VERSION 5.7 ;
  NOWIREEXTENSIONATPIN ON ;
  DIVIDERCHAR "/" ;
  BUSBITCHARS "[]" ;
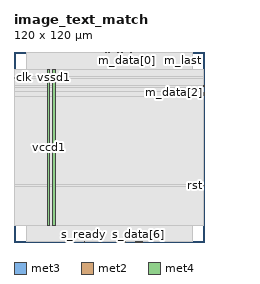
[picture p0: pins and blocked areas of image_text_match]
MACRO image_text_match
  CLASS BLOCK ;
  FOREIGN image_text_match ;
  ORIGIN 0.000 0.000 ;
  SIZE 120.000 BY 120.000 ;
  PIN clk
    DIRECTION INPUT ;
    USE SIGNAL ;
    ANTENNAGATEAREA 1.286700 ;
    ANTENNADIFFAREA 0.434700 ;
    PORT
      LAYER met3 ;
        RECT 0.000 103.400 0.600 104.000 ;
    END
  END clk
  PIN m_data[0]
    DIRECTION OUTPUT ;
    USE SIGNAL ;
    ANTENNADIFFAREA 0.702900 ;
    PORT
      LAYER met2 ;
        RECT 70.930 119.720 71.210 120.000 ;
    END
  END m_data[0]
  PIN m_data[1]
    DIRECTION OUTPUT ;
    USE SIGNAL ;
    ANTENNADIFFAREA 0.702900 ;
    PORT
      LAYER met2 ;
        RECT 68.170 119.720 68.450 120.000 ;
    END
  END m_data[1]
  PIN m_data[2]
    DIRECTION OUTPUT ;
    USE SIGNAL ;
    ANTENNADIFFAREA 0.702900 ;
    PORT
      LAYER met3 ;
        RECT 119.400 93.880 120.000 94.480 ;
    END
  END m_data[2]
  PIN m_data[3]
    DIRECTION OUTPUT ;
    USE SIGNAL ;
    ANTENNADIFFAREA 0.702900 ;
    PORT
      LAYER met3 ;
        RECT 119.400 92.520 120.000 93.120 ;
    END
  END m_data[3]
  PIN m_data[4]
    DIRECTION OUTPUT ;
    USE SIGNAL ;
    ANTENNADIFFAREA 0.702900 ;
    PORT
      LAYER met2 ;
        RECT 94.850 119.720 95.130 120.000 ;
    END
  END m_data[4]
  PIN m_data[5]
    DIRECTION OUTPUT ;
    USE SIGNAL ;
    ANTENNADIFFAREA 0.702900 ;
    PORT
      LAYER met3 ;
        RECT 119.400 97.960 120.000 98.560 ;
    END
  END m_data[5]
  PIN m_data[6]
    DIRECTION OUTPUT ;
    USE SIGNAL ;
    ANTENNADIFFAREA 0.702900 ;
    PORT
      LAYER met2 ;
        RECT 73.690 119.720 73.970 120.000 ;
    END
  END m_data[6]
  PIN m_data[7]
    DIRECTION OUTPUT ;
    USE SIGNAL ;
    ANTENNADIFFAREA 0.702900 ;
    PORT
      LAYER met2 ;
        RECT 72.770 119.720 73.050 120.000 ;
    END
  END m_data[7]
  PIN m_last
    DIRECTION OUTPUT ;
    USE SIGNAL ;
    ANTENNADIFFAREA 0.702900 ;
    PORT
      LAYER met2 ;
        RECT 106.810 119.720 107.090 120.000 ;
    END
  END m_last
  PIN m_ready
    DIRECTION INPUT ;
    USE SIGNAL ;
    ANTENNAGATEAREA 0.647700 ;
    ANTENNADIFFAREA 0.434700 ;
    PORT
      LAYER met2 ;
        RECT 58.050 119.720 58.330 120.000 ;
    END
  END m_ready
  PIN m_valid
    DIRECTION OUTPUT ;
    USE SIGNAL ;
    ANTENNADIFFAREA 0.702900 ;
    PORT
      LAYER met2 ;
        RECT 59.890 119.720 60.170 120.000 ;
    END
  END m_valid
  PIN rst
    DIRECTION INPUT ;
    USE SIGNAL ;
    ANTENNAGATEAREA 0.647700 ;
    ANTENNADIFFAREA 0.434700 ;
    PORT
      LAYER met3 ;
        RECT 119.400 35.400 120.000 36.000 ;
    END
  END rst
  PIN s_data[0]
    DIRECTION INPUT ;
    USE SIGNAL ;
    ANTENNAGATEAREA 0.647700 ;
    ANTENNADIFFAREA 0.434700 ;
    PORT
      LAYER met2 ;
        RECT 54.370 0.000 54.650 0.280 ;
    END
  END s_data[0]
  PIN s_data[1]
    DIRECTION INPUT ;
    USE SIGNAL ;
    ANTENNAGATEAREA 0.647700 ;
    ANTENNADIFFAREA 0.434700 ;
    PORT
      LAYER met2 ;
        RECT 70.010 0.000 70.290 0.280 ;
    END
  END s_data[1]
  PIN s_data[2]
    DIRECTION INPUT ;
    USE SIGNAL ;
    ANTENNAGATEAREA 0.647700 ;
    ANTENNADIFFAREA 0.434700 ;
    PORT
      LAYER met2 ;
        RECT 77.370 0.000 77.650 0.280 ;
    END
  END s_data[2]
  PIN s_data[3]
    DIRECTION INPUT ;
    USE SIGNAL ;
    ANTENNAGATEAREA 0.647700 ;
    ANTENNADIFFAREA 0.434700 ;
    PORT
      LAYER met2 ;
        RECT 76.450 0.000 76.730 0.280 ;
    END
  END s_data[3]
  PIN s_data[4]
    DIRECTION INPUT ;
    USE SIGNAL ;
    ANTENNAGATEAREA 0.647700 ;
    ANTENNADIFFAREA 0.434700 ;
    PORT
      LAYER met2 ;
        RECT 79.210 0.000 79.490 0.280 ;
    END
  END s_data[4]
  PIN s_data[5]
    DIRECTION INPUT ;
    USE SIGNAL ;
    ANTENNAGATEAREA 0.647700 ;
    ANTENNADIFFAREA 0.434700 ;
    PORT
      LAYER met2 ;
        RECT 81.050 0.000 81.330 0.280 ;
    END
  END s_data[5]
  PIN s_data[6]
    DIRECTION INPUT ;
    USE SIGNAL ;
    ANTENNAGATEAREA 0.647700 ;
    ANTENNADIFFAREA 0.434700 ;
    PORT
      LAYER met2 ;
        RECT 78.290 0.000 78.570 0.280 ;
    END
  END s_data[6]
  PIN s_data[7]
    DIRECTION INPUT ;
    USE SIGNAL ;
    ANTENNAGATEAREA 0.647700 ;
    ANTENNADIFFAREA 0.434700 ;
    PORT
      LAYER met2 ;
        RECT 80.130 0.000 80.410 0.280 ;
    END
  END s_data[7]
  PIN s_last
    DIRECTION INPUT ;
    USE SIGNAL ;
    ANTENNAGATEAREA 0.647700 ;
    ANTENNADIFFAREA 0.434700 ;
    PORT
      LAYER met2 ;
        RECT 65.410 119.720 65.690 120.000 ;
    END
  END s_last
  PIN s_ready
    DIRECTION OUTPUT ;
    USE SIGNAL ;
    ANTENNADIFFAREA 0.702900 ;
    PORT
      LAYER met2 ;
        RECT 44.250 0.000 44.530 0.280 ;
    END
  END s_ready
  PIN s_valid
    DIRECTION INPUT ;
    USE SIGNAL ;
    ANTENNAGATEAREA 0.647700 ;
    ANTENNADIFFAREA 0.434700 ;
    PORT
      LAYER met2 ;
        RECT 52.530 119.720 52.810 120.000 ;
    END
  END s_valid
  PIN vccd1
    DIRECTION INOUT ;
    USE POWER ;
    PORT
      LAYER met4 ;
        RECT 21.040 10.640 22.640 109.040 ;
    END
  END vccd1
  PIN vssd1
    DIRECTION INOUT ;
    USE GROUND ;
    PORT
      LAYER met4 ;
        RECT 24.340 10.640 25.940 109.040 ;
    END
  END vssd1
  OBS
      LAYER nwell ;
        RECT 5.330 10.795 114.270 108.885 ;
      LAYER li1 ;
        RECT 5.520 10.795 114.080 108.885 ;
      LAYER met1 ;
        RECT 5.520 10.640 114.080 109.040 ;
      LAYER met2 ;
        RECT 7.920 119.440 52.250 119.720 ;
        RECT 53.090 119.440 57.770 119.720 ;
        RECT 58.610 119.440 59.610 119.720 ;
        RECT 60.450 119.440 65.130 119.720 ;
        RECT 65.970 119.440 67.890 119.720 ;
        RECT 68.730 119.440 70.650 119.720 ;
        RECT 71.490 119.440 72.490 119.720 ;
        RECT 73.330 119.440 73.410 119.720 ;
        RECT 74.250 119.440 94.570 119.720 ;
        RECT 95.410 119.440 106.530 119.720 ;
        RECT 107.370 119.440 112.610 119.720 ;
        RECT 7.920 0.560 112.610 119.440 ;
        RECT 7.920 0.280 43.970 0.560 ;
        RECT 44.810 0.280 54.090 0.560 ;
        RECT 54.930 0.280 69.730 0.560 ;
        RECT 70.570 0.280 76.170 0.560 ;
        RECT 77.010 0.280 77.090 0.560 ;
        RECT 77.930 0.280 78.010 0.560 ;
        RECT 78.850 0.280 78.930 0.560 ;
        RECT 79.770 0.280 79.850 0.560 ;
        RECT 80.690 0.280 80.770 0.560 ;
        RECT 81.610 0.280 112.610 0.560 ;
      LAYER met3 ;
        RECT 0.600 104.400 119.400 108.965 ;
        RECT 1.000 103.000 119.400 104.400 ;
        RECT 0.600 98.960 119.400 103.000 ;
        RECT 0.600 97.560 119.000 98.960 ;
        RECT 0.600 94.880 119.400 97.560 ;
        RECT 0.600 92.120 119.000 94.880 ;
        RECT 0.600 36.400 119.400 92.120 ;
        RECT 0.600 35.000 119.000 36.400 ;
        RECT 0.600 10.715 119.400 35.000 ;
  END
END image_text_match
END LIBRARY

